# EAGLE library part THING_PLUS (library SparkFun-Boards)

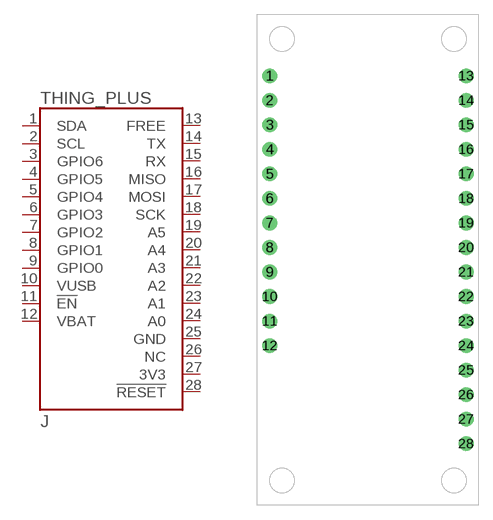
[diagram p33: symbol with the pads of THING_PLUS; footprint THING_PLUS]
Designator prefix J

## THING_PLUS  [THING_PLUS]
1  SDA
2  SCL
3  GPIO6
4  GPIO5
5  GPIO4
6  GPIO3
7  GPIO2
8  GPIO1
9  GPIO0
10  VUSB
11  !EN
12  VBAT
13  FREE
14  TX
15  RX
16  MISO
17  MOSI
18  SCK
19  A5
20  A4
21  A3
22  A2
23  A1
24  A0
25  GND
26  NC
27  3V3
28  !RESET

## Footprint THING_PLUS (pad centres in mm)
drill 1.016: 1 -10.16,19.05; 2 -10.16,16.51; 3 -10.16,13.97; 4 -10.16,11.43; 5 -10.16,8.89; 6 -10.16,6.35; 7 -10.16,3.81; 8 -10.16,1.27; 9 -10.16,-1.27; 10 -10.16,-3.81; 11 -10.16,-6.35; 12 -10.16,-8.89; 13 10.16,19.05; 14 10.16,16.51; 15 10.16,13.97; 16 10.16,11.43; 17 10.16,8.89; 18 10.16,6.35; 19 10.16,3.81; 20 10.16,1.27; 21 10.16,-1.27; 22 10.16,-3.81; 23 10.16,-6.35; 24 10.16,-8.89; 25 10.16,-11.43; 26 10.16,-13.97; 27 10.16,-16.51; 28 10.16,-19.05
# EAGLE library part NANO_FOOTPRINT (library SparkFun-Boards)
Generic Nano Footprint

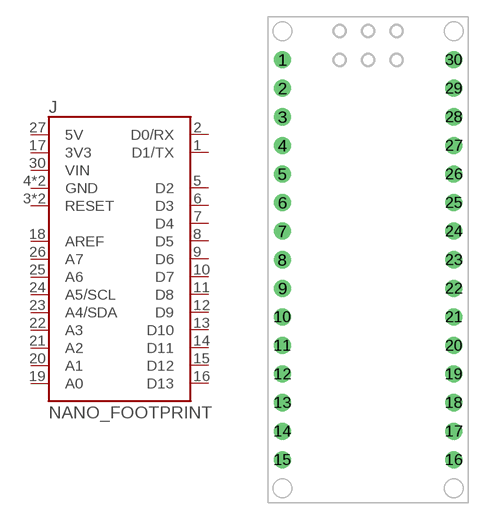
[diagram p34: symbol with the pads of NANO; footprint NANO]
Designator prefix J

## NANO_FOOTPRINT  [NANO]
1  D1/TX
2  D0/RX
3  RESET
4  GND
5  D2
6  D3
7  D4
8  D5
9  D6
10  D7
11  D8
12  D9
13  D10
14  D11
15  D12
16  D13
17  3V3
18  AREF
19  A0
20  A1
21  A2
22  A3
23  A4/SDA
24  A5/SCL
25  A6
26  A7
27  5V
28  RESET
29  GND
30  VIN

## Footprint NANO (pad centres in mm)
Arduino Nano Footprint
drill 1.016: 1 -7.62,17.78; 2 -7.62,15.24; 3 -7.62,12.7; 4 -7.62,10.16; 5 -7.62,7.62; 6 -7.62,5.08; 7 -7.62,2.54; 8 -7.62,0; 9 -7.62,-2.54; 10 -7.62,-5.08; 11 -7.62,-7.62; 12 -7.62,-10.16; 13 -7.62,-12.7; 14 -7.62,-15.24; 15 -7.62,-17.78; 16 7.62,-17.78; 17 7.62,-15.24; 18 7.62,-12.7; 19 7.62,-10.16; 20 7.62,-7.62; 21 7.62,-5.08; 22 7.62,-2.54; 23 7.62,0; 24 7.62,2.54; 25 7.62,5.08; 26 7.62,7.62; 27 7.62,10.16; 28 7.62,12.7; 29 7.62,15.24; 30 7.62,17.78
